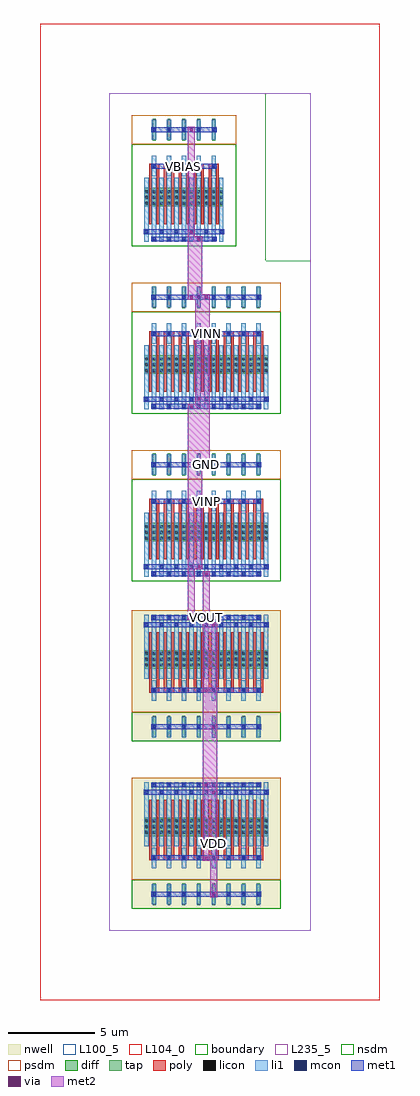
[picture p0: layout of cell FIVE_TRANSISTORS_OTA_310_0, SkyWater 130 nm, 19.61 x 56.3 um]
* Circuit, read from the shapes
.subckt FIVE_TRANSISTORS_OTA_310_0 GND VBIAS VDD VINN VINP VOUT
XM1 n1 VINP n2 GND sky130_fd_pr__nfet_01v8 w=1.05 l=0.15 m=16
XM2 VOUT VINN n2 GND sky130_fd_pr__nfet_01v8 w=1.05 l=0.15 m=16
XM3 n2 VBIAS GND GND sky130_fd_pr__nfet_01v8 w=1.05 l=0.15 m=10
XM4 n1 n1 VDD VDD sky130_fd_pr__pfet_01v8 w=1.05 l=0.15 m=16
XM5 VOUT n1 VDD VDD sky130_fd_pr__pfet_01v8 w=1.05 l=0.15 m=16
.ends

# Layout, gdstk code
import gdstk
lib = gdstk.Library(unit=1e-6, precision=1e-09)
def R(c, l, rs):  # rectangles x0, y0, x1, y1
    for r in rs: c.add(gdstk.rectangle(r[:2], r[2:], *l))
def A(c, l, x, y, w, h, nx, ny, dx, dy):  # array of equal rectangles
    R(c, l, [(x+i*dx, y+j*dy, x+i*dx+w, y+j*dy+h) for i in range(nx) for j in range(ny)])
def P(c, l, *ps):  # polygons
    for p in ps: c.add(gdstk.Polygon(p, *l))
nwell = (64, 20)
diff = (65, 20)
tap = (65, 44)
poly = (66, 20)
licon = (66, 44)
li1 = (67, 20)
mcon = (67, 44)
met1 = (68, 20)
via = (68, 44)
met2 = (69, 20)
nsdm = (93, 44)
psdm = (94, 20)
L100_5 = (100, 5)
L104_0 = (104, 0)
boundary = (235, 4)
L235_5 = (235, 5)

dcl_pmos_s_17530687_x8_y = lib.new_cell('DCL_PMOS_S_17530687_X8_Y1_1746750583')
R(dcl_pmos_s_17530687_x8_y, nwell, [(1.29,0.84,9.89,8.4)])
R(dcl_pmos_s_17530687_x8_y, diff, [(2.025,3.15,9.155,4.2)])
A(dcl_pmos_s_17530687_x8_y, tap, 2.495, 6.915, 0.17, 1.29, 8, 1, 0.86, 0)
A(dcl_pmos_s_17530687_x8_y, poly, 2.29, 2.1, 0.15, 3.36, 16, 1, 0.43, 0)
A(dcl_pmos_s_17530687_x8_y, poly, 2.29, 5.325, 0.58, 0.27, 8, 1, 0.86, 0)
A(dcl_pmos_s_17530687_x8_y, licon, 2.065, 3.23, 0.17, 0.17, 3, 3, 0.43, 0.34)
A(dcl_pmos_s_17530687_x8_y, licon, 2.925, 3.23, 0.17, 0.17, 3, 3, 0.43, 0.34)
A(dcl_pmos_s_17530687_x8_y, licon, 3.785, 3.23, 0.17, 0.17, 3, 3, 0.43, 0.34)
A(dcl_pmos_s_17530687_x8_y, licon, 4.645, 3.23, 0.17, 0.17, 3, 3, 0.43, 0.34)
A(dcl_pmos_s_17530687_x8_y, licon, 5.505, 3.23, 0.17, 0.17, 3, 3, 0.43, 0.34)
A(dcl_pmos_s_17530687_x8_y, licon, 6.365, 3.23, 0.17, 0.17, 3, 3, 0.43, 0.34)
A(dcl_pmos_s_17530687_x8_y, licon, 7.225, 3.23, 0.17, 0.17, 3, 3, 0.43, 0.34)
A(dcl_pmos_s_17530687_x8_y, licon, 8.085, 3.23, 0.17, 0.17, 3, 3, 0.43, 0.34)
A(dcl_pmos_s_17530687_x8_y, licon, 2.495, 5.375, 0.17, 0.17, 8, 2, 0.86, 2.1)
A(dcl_pmos_s_17530687_x8_y, li1, 2.025, 1.09, 0.25, 3.7, 17, 1, 0.43, 0)
A(dcl_pmos_s_17530687_x8_y, li1, 2.455, 4.87, 0.25, 1.18, 8, 2, 0.86, 2.1)
A(dcl_pmos_s_17530687_x8_y, mcon, 2.495, 1.175, 0.17, 0.17, 8, 2, 0.86, 4.2)
A(dcl_pmos_s_17530687_x8_y, mcon, 2.065, 1.595, 0.17, 0.17, 9, 1, 0.86, 0)
A(dcl_pmos_s_17530687_x8_y, mcon, 2.495, 7.475, 0.17, 0.17, 8, 1, 0.86, 0)
R(dcl_pmos_s_17530687_x8_y, met1, [(2.41,1.12,8.77,1.4), (1.98,1.54,9.2,1.82), (2.41,5.32,8.77,5.6), (2.41,7.42,8.77,7.7)])
R(dcl_pmos_s_17530687_x8_y, via, [(5.515,1.185,5.665,1.335), (5.945,1.605,6.095,1.755), (5.515,5.385,5.665,5.535), (5.945,7.485,6.095,7.635)])
R(dcl_pmos_s_17530687_x8_y, met2, [(5.39,1.1,5.79,5.62), (5.82,1.52,6.22,7.72)])
R(dcl_pmos_s_17530687_x8_y, nsdm, [(1.29,6.72,9.89,8.4)])
R(dcl_pmos_s_17530687_x8_y, psdm, [(1.29,0.84,9.89,6.72)])
R(dcl_pmos_s_17530687_x8_y, L100_5, [(0,0,11.61,9.66)])
R(dcl_pmos_s_17530687_x8_y, boundary, [(0,0,11.61,9.66)])

nmos_s_52209288_x5_y1_17 = lib.new_cell('NMOS_S_52209288_X5_Y1_1746750586')
R(nmos_s_52209288_x5_y1_17, diff, [(2.025,3.15,6.575,4.2)])
A(nmos_s_52209288_x5_y1_17, tap, 2.495, 6.915, 0.17, 1.29, 5, 1, 0.86, 0)
A(nmos_s_52209288_x5_y1_17, poly, 2.29, 2.1, 0.15, 3.36, 10, 1, 0.43, 0)
A(nmos_s_52209288_x5_y1_17, poly, 2.29, 5.325, 0.58, 0.27, 5, 1, 0.86, 0)
A(nmos_s_52209288_x5_y1_17, licon, 2.065, 3.23, 0.17, 0.17, 3, 3, 0.43, 0.34)
A(nmos_s_52209288_x5_y1_17, licon, 2.925, 3.23, 0.17, 0.17, 3, 3, 0.43, 0.34)
A(nmos_s_52209288_x5_y1_17, licon, 3.785, 3.23, 0.17, 0.17, 3, 3, 0.43, 0.34)
A(nmos_s_52209288_x5_y1_17, licon, 4.645, 3.23, 0.17, 0.17, 3, 3, 0.43, 0.34)
A(nmos_s_52209288_x5_y1_17, licon, 5.505, 3.23, 0.17, 0.17, 3, 3, 0.43, 0.34)
A(nmos_s_52209288_x5_y1_17, licon, 2.495, 5.375, 0.17, 0.17, 5, 2, 0.86, 2.1)
A(nmos_s_52209288_x5_y1_17, li1, 2.025, 1.09, 0.25, 3.7, 11, 1, 0.43, 0)
A(nmos_s_52209288_x5_y1_17, li1, 2.455, 4.87, 0.25, 1.18, 5, 2, 0.86, 2.1)
A(nmos_s_52209288_x5_y1_17, mcon, 2.495, 1.175, 0.17, 0.17, 5, 2, 0.86, 4.2)
A(nmos_s_52209288_x5_y1_17, mcon, 2.065, 1.595, 0.17, 0.17, 6, 1, 0.86, 0)
A(nmos_s_52209288_x5_y1_17, mcon, 2.495, 7.475, 0.17, 0.17, 5, 1, 0.86, 0)
R(nmos_s_52209288_x5_y1_17, met1, [(2.41,1.12,6.19,1.4), (1.98,1.54,6.62,1.82), (2.41,5.32,6.19,5.6), (2.41,7.42,6.19,7.7)])
R(nmos_s_52209288_x5_y1_17, via, [(4.655,1.605,4.805,1.755), (4.655,7.485,4.805,7.635)])
R(nmos_s_52209288_x5_y1_17, met2, [(4.53,1.52,4.93,7.72)])
R(nmos_s_52209288_x5_y1_17, nsdm, [(1.29,0.84,7.31,6.72)])
R(nmos_s_52209288_x5_y1_17, psdm, [(1.29,6.72,7.31,8.4)])
R(nmos_s_52209288_x5_y1_17, L100_5, [(0,0,9.03,9.66)])
R(nmos_s_52209288_x5_y1_17, boundary, [(0,0,9.03,9.66)])

pmos_s_93182587_x8_y1_17 = lib.new_cell('PMOS_S_93182587_X8_Y1_1746750587')
R(pmos_s_93182587_x8_y1_17, nwell, [(1.29,0.84,9.89,8.4)])
R(pmos_s_93182587_x8_y1_17, diff, [(2.025,3.15,9.155,4.2)])
A(pmos_s_93182587_x8_y1_17, tap, 2.495, 6.915, 0.17, 1.29, 8, 1, 0.86, 0)
A(pmos_s_93182587_x8_y1_17, poly, 2.29, 2.1, 0.15, 3.36, 16, 1, 0.43, 0)
A(pmos_s_93182587_x8_y1_17, poly, 2.29, 5.325, 0.58, 0.27, 8, 1, 0.86, 0)
A(pmos_s_93182587_x8_y1_17, licon, 2.065, 3.23, 0.17, 0.17, 3, 3, 0.43, 0.34)
A(pmos_s_93182587_x8_y1_17, licon, 2.925, 3.23, 0.17, 0.17, 3, 3, 0.43, 0.34)
A(pmos_s_93182587_x8_y1_17, licon, 3.785, 3.23, 0.17, 0.17, 3, 3, 0.43, 0.34)
A(pmos_s_93182587_x8_y1_17, licon, 4.645, 3.23, 0.17, 0.17, 3, 3, 0.43, 0.34)
A(pmos_s_93182587_x8_y1_17, licon, 5.505, 3.23, 0.17, 0.17, 3, 3, 0.43, 0.34)
A(pmos_s_93182587_x8_y1_17, licon, 6.365, 3.23, 0.17, 0.17, 3, 3, 0.43, 0.34)
A(pmos_s_93182587_x8_y1_17, licon, 7.225, 3.23, 0.17, 0.17, 3, 3, 0.43, 0.34)
A(pmos_s_93182587_x8_y1_17, licon, 8.085, 3.23, 0.17, 0.17, 3, 3, 0.43, 0.34)
A(pmos_s_93182587_x8_y1_17, licon, 2.495, 5.375, 0.17, 0.17, 8, 2, 0.86, 2.1)
A(pmos_s_93182587_x8_y1_17, li1, 2.025, 1.09, 0.25, 3.7, 17, 1, 0.43, 0)
A(pmos_s_93182587_x8_y1_17, li1, 2.455, 4.87, 0.25, 1.18, 8, 2, 0.86, 2.1)
A(pmos_s_93182587_x8_y1_17, mcon, 2.495, 1.175, 0.17, 0.17, 8, 2, 0.86, 4.2)
A(pmos_s_93182587_x8_y1_17, mcon, 2.065, 1.595, 0.17, 0.17, 9, 1, 0.86, 0)
A(pmos_s_93182587_x8_y1_17, mcon, 2.495, 7.475, 0.17, 0.17, 8, 1, 0.86, 0)
R(pmos_s_93182587_x8_y1_17, met1, [(2.41,1.12,8.77,1.4), (1.98,1.54,9.2,1.82), (2.41,5.32,8.77,5.6), (2.41,7.42,8.77,7.7)])
R(pmos_s_93182587_x8_y1_17, via, [(5.945,1.605,6.095,1.755), (5.945,7.485,6.095,7.635)])
R(pmos_s_93182587_x8_y1_17, met2, [(5.82,1.52,6.22,7.72)])
R(pmos_s_93182587_x8_y1_17, nsdm, [(1.29,6.72,9.89,8.4)])
R(pmos_s_93182587_x8_y1_17, psdm, [(1.29,0.84,9.89,6.72)])
R(pmos_s_93182587_x8_y1_17, L100_5, [(0,0,11.61,9.66)])
R(pmos_s_93182587_x8_y1_17, boundary, [(0,0,11.61,9.66)])

nmos_4t_3160949_x8_y1_17 = lib.new_cell('NMOS_4T_3160949_X8_Y1_1746750585')
R(nmos_4t_3160949_x8_y1_17, diff, [(2.025,3.15,9.155,4.2)])
A(nmos_4t_3160949_x8_y1_17, tap, 2.495, 6.915, 0.17, 1.29, 8, 1, 0.86, 0)
A(nmos_4t_3160949_x8_y1_17, poly, 2.29, 2.1, 0.15, 3.36, 16, 1, 0.43, 0)
A(nmos_4t_3160949_x8_y1_17, poly, 2.29, 5.325, 0.58, 0.27, 8, 1, 0.86, 0)
A(nmos_4t_3160949_x8_y1_17, licon, 2.065, 3.23, 0.17, 0.17, 3, 3, 0.43, 0.34)
A(nmos_4t_3160949_x8_y1_17, licon, 2.925, 3.23, 0.17, 0.17, 3, 3, 0.43, 0.34)
A(nmos_4t_3160949_x8_y1_17, licon, 3.785, 3.23, 0.17, 0.17, 3, 3, 0.43, 0.34)
A(nmos_4t_3160949_x8_y1_17, licon, 4.645, 3.23, 0.17, 0.17, 3, 3, 0.43, 0.34)
A(nmos_4t_3160949_x8_y1_17, licon, 5.505, 3.23, 0.17, 0.17, 3, 3, 0.43, 0.34)
A(nmos_4t_3160949_x8_y1_17, licon, 6.365, 3.23, 0.17, 0.17, 3, 3, 0.43, 0.34)
A(nmos_4t_3160949_x8_y1_17, licon, 7.225, 3.23, 0.17, 0.17, 3, 3, 0.43, 0.34)
A(nmos_4t_3160949_x8_y1_17, licon, 8.085, 3.23, 0.17, 0.17, 3, 3, 0.43, 0.34)
A(nmos_4t_3160949_x8_y1_17, licon, 2.495, 5.375, 0.17, 0.17, 8, 2, 0.86, 2.1)
A(nmos_4t_3160949_x8_y1_17, li1, 2.025, 1.09, 0.25, 3.7, 17, 1, 0.43, 0)
A(nmos_4t_3160949_x8_y1_17, li1, 2.455, 4.87, 0.25, 1.18, 8, 2, 0.86, 2.1)
A(nmos_4t_3160949_x8_y1_17, mcon, 2.495, 1.175, 0.17, 0.17, 8, 2, 0.86, 4.2)
A(nmos_4t_3160949_x8_y1_17, mcon, 2.065, 1.595, 0.17, 0.17, 9, 1, 0.86, 0)
A(nmos_4t_3160949_x8_y1_17, mcon, 2.495, 7.475, 0.17, 0.17, 8, 1, 0.86, 0)
R(nmos_4t_3160949_x8_y1_17, met1, [(2.41,1.12,8.77,1.4), (1.98,1.54,9.2,1.82), (2.41,5.32,8.77,5.6), (2.41,7.42,8.77,7.7)])
R(nmos_4t_3160949_x8_y1_17, nsdm, [(1.29,0.84,9.89,6.72)])
R(nmos_4t_3160949_x8_y1_17, psdm, [(1.29,6.72,9.89,8.4)])
R(nmos_4t_3160949_x8_y1_17, L100_5, [(0,0,11.61,9.66)])
R(nmos_4t_3160949_x8_y1_17, boundary, [(0,0,11.61,9.66)])

nmos_4t_21140221_x8_y1_1 = lib.new_cell('NMOS_4T_21140221_X8_Y1_1746750584')
R(nmos_4t_21140221_x8_y1_1, diff, [(2.025,3.15,9.155,4.2)])
A(nmos_4t_21140221_x8_y1_1, tap, 2.495, 6.915, 0.17, 1.29, 8, 1, 0.86, 0)
A(nmos_4t_21140221_x8_y1_1, poly, 2.29, 2.1, 0.15, 3.36, 16, 1, 0.43, 0)
A(nmos_4t_21140221_x8_y1_1, poly, 2.29, 5.325, 0.58, 0.27, 8, 1, 0.86, 0)
A(nmos_4t_21140221_x8_y1_1, licon, 2.065, 3.23, 0.17, 0.17, 3, 3, 0.43, 0.34)
A(nmos_4t_21140221_x8_y1_1, licon, 2.925, 3.23, 0.17, 0.17, 3, 3, 0.43, 0.34)
A(nmos_4t_21140221_x8_y1_1, licon, 3.785, 3.23, 0.17, 0.17, 3, 3, 0.43, 0.34)
A(nmos_4t_21140221_x8_y1_1, licon, 4.645, 3.23, 0.17, 0.17, 3, 3, 0.43, 0.34)
A(nmos_4t_21140221_x8_y1_1, licon, 5.505, 3.23, 0.17, 0.17, 3, 3, 0.43, 0.34)
A(nmos_4t_21140221_x8_y1_1, licon, 6.365, 3.23, 0.17, 0.17, 3, 3, 0.43, 0.34)
A(nmos_4t_21140221_x8_y1_1, licon, 7.225, 3.23, 0.17, 0.17, 3, 3, 0.43, 0.34)
A(nmos_4t_21140221_x8_y1_1, licon, 8.085, 3.23, 0.17, 0.17, 3, 3, 0.43, 0.34)
A(nmos_4t_21140221_x8_y1_1, licon, 2.495, 5.375, 0.17, 0.17, 8, 2, 0.86, 2.1)
A(nmos_4t_21140221_x8_y1_1, li1, 2.025, 1.09, 0.25, 3.7, 17, 1, 0.43, 0)
A(nmos_4t_21140221_x8_y1_1, li1, 2.455, 4.87, 0.25, 1.18, 8, 2, 0.86, 2.1)
A(nmos_4t_21140221_x8_y1_1, mcon, 2.495, 1.175, 0.17, 0.17, 8, 2, 0.86, 4.2)
A(nmos_4t_21140221_x8_y1_1, mcon, 2.065, 1.595, 0.17, 0.17, 9, 1, 0.86, 0)
A(nmos_4t_21140221_x8_y1_1, mcon, 2.495, 7.475, 0.17, 0.17, 8, 1, 0.86, 0)
R(nmos_4t_21140221_x8_y1_1, met1, [(2.41,1.12,8.77,1.4), (1.98,1.54,9.2,1.82), (2.41,5.32,8.77,5.6), (2.41,7.42,8.77,7.7)])
R(nmos_4t_21140221_x8_y1_1, nsdm, [(1.29,0.84,9.89,6.72)])
R(nmos_4t_21140221_x8_y1_1, psdm, [(1.29,6.72,9.89,8.4)])
R(nmos_4t_21140221_x8_y1_1, L100_5, [(0,0,11.61,9.66)])
R(nmos_4t_21140221_x8_y1_1, boundary, [(0,0,11.61,9.66)])

five_transistors_ota_310 = lib.new_cell('FIVE_TRANSISTORS_OTA_310_0')
R(five_transistors_ota_310, met1, [(5.43,13.72,5.75,14), (5.43,13.72,5.75,14), (5.43,13.72,5.75,14), (5.43,13.72,5.75,14), (4.57,17.92,4.89,18.2), (4.57,17.92,4.89,18.2), (5.43,20.44,5.75,20.72), (5.43,20.44,5.75,20.72), (5,20.86,5.32,21.14), (5,20.86,5.32,21.14), (5,20.86,5.32,21.14), (5,20.86,5.32,21.14), (5.43,26.74,5.75,27.02), (5.43,26.74,5.75,27.02), (5.43,26.74,5.75,27.02), (5.43,26.74,5.75,27.02), (4.57,30.1,4.89,30.38), (4.57,30.1,4.89,30.38), (5,30.52,5.32,30.8), (5,30.52,5.32,30.8), (5,30.52,5.32,30.8), (5,30.52,5.32,30.8), (4.57,36.4,4.89,36.68), (4.57,36.4,4.89,36.68), (5.43,36.4,5.75,36.68), (5.43,36.4,5.75,36.68), (5.43,36.4,5.75,36.68), (5.43,36.4,5.75,36.68), (5,39.76,5.32,40.04), (5,39.76,5.32,40.04)])
P(five_transistors_ota_310, met1, [(0,0),(0,0),(0,0),(0,0)],
  [(0,0),(0,0),(0,0),(0,0)],
  [(0,0),(0,0),(0,0),(0,0)],
  [(0,0),(0,0),(0,0),(0,0)],
  [(0,0),(0,0),(0,0),(0,0)],
  [(0,0),(0,0),(0,0),(0,0)],
  [(0,0),(0,0),(0,0),(0,0)],
  [(0,0),(0,0),(0,0),(0,0)],
  [(0,0),(0,0),(0,0),(0,0)],
  [(0,0),(0,0),(0,0),(0,0)],
  [(0,0),(0,0),(0,0),(0,0)],
  [(0,0),(0,0),(0,0),(0,0)],
  [(0,0),(0,0),(0,0),(0,0)],
  [(0,0),(0,0),(0,0),(0,0)],
  [(0,0),(0,0),(0,0),(0,0)],
  [(0,0),(0,0),(0,0),(0,0)],
  [(0,0),(0,0),(0,0),(0,0)])
R(five_transistors_ota_310, via, [(5.515,13.785,5.665,13.935), (5.515,13.785,5.665,13.935), (5.515,13.785,5.665,13.935), (5.515,13.785,5.665,13.935), (4.655,17.985,4.805,18.135), (4.655,17.985,4.805,18.135), (5.515,20.505,5.665,20.655), (5.515,20.505,5.665,20.655), (5.085,20.925,5.235,21.075), (5.085,20.925,5.235,21.075), (5.085,20.925,5.235,21.075), (5.085,20.925,5.235,21.075), (5.515,26.805,5.665,26.955), (5.515,26.805,5.665,26.955), (5.515,26.805,5.665,26.955), (5.515,26.805,5.665,26.955), (4.655,30.165,4.805,30.315), (4.655,30.165,4.805,30.315), (5.085,30.585,5.235,30.735), (5.085,30.585,5.235,30.735), (5.085,30.585,5.235,30.735), (5.085,30.585,5.235,30.735), (4.655,36.465,4.805,36.615), (4.655,36.465,4.805,36.615), (5.515,36.465,5.665,36.615), (5.515,36.465,5.665,36.615), (5.515,36.465,5.665,36.615), (5.515,36.465,5.665,36.615), (5.085,39.825,5.235,39.975), (5.085,39.825,5.235,39.975)])
R(five_transistors_ota_310, met2, [(5.82,7.98,6.22,11.76), (5.39,8.4,5.79,13.86), (5.39,13.7,5.79,14.02), (5.39,13.7,5.79,14.02), (5.39,13.7,5.79,14.02), (5.39,13.7,5.79,14.02), (5.39,13.86,5.79,20.58), (4.53,17.9,4.93,18.22), (4.53,17.9,4.93,18.22), (4.53,18.06,4.93,30.24), (5.39,20.42,5.79,20.74), (5.39,20.42,5.79,20.74), (4.96,20.84,5.36,21.16), (4.96,20.84,5.36,21.16), (4.96,20.84,5.36,21.16), (4.96,20.84,5.36,21.16), (4.96,21,5.36,30.66), (5.39,26.72,5.79,27.04), (5.39,26.72,5.79,27.04), (5.39,26.72,5.79,27.04), (5.39,26.72,5.79,27.04), (5.39,26.88,5.79,36.54), (4.53,30.08,4.93,30.4), (4.53,30.08,4.93,30.4), (4.96,30.5,5.36,30.82), (4.96,30.5,5.36,30.82), (4.96,30.5,5.36,30.82), (4.96,30.5,5.36,30.82), (4.96,30.66,5.36,39.9), (4.53,36.38,4.93,36.7), (4.53,36.38,4.93,36.7), (5.39,36.38,5.79,36.7), (5.39,36.38,5.79,36.7), (5.39,36.38,5.79,36.7), (5.39,36.38,5.79,36.7), (4.53,36.54,4.93,40.32), (4.96,39.74,5.36,40.06), (4.96,39.74,5.36,40.06)])
P(five_transistors_ota_310, met2, [(0,0),(0,0),(0,0),(0,0)],
  [(0,0),(0,0),(0,0),(0,0)],
  [(0,0),(0,0),(0,0),(0,0)],
  [(0,0),(0,0),(0,0),(0,0)],
  [(0,0),(0,0),(0,0),(0,0)])
R(five_transistors_ota_310, L104_0, [(-4,-4,15.61,52.3)])
R(five_transistors_ota_310, L235_5, [(0,0,11.61,48.3)])
five_transistors_ota_310.add(gdstk.Reference(dcl_pmos_s_17530687_x8_y, (0,9.66), x_reflection=True))
five_transistors_ota_310.add(gdstk.Reference(nmos_s_52209288_x5_y1_17, (0,38.64)))
five_transistors_ota_310.add(gdstk.Reference(pmos_s_93182587_x8_y1_17, (0,19.32), x_reflection=True))
five_transistors_ota_310.add(gdstk.Reference(nmos_4t_3160949_x8_y1_17, (0,28.98)))
five_transistors_ota_310.add(gdstk.Reference(nmos_4t_21140221_x8_y1_1, (0,19.32)))
five_transistors_ota_310.add(gdstk.Label('VDD', (6.02,5.04), layer=69, texttype=5))
five_transistors_ota_310.add(gdstk.Label('VBIAS', (4.3,44.1), layer=68, texttype=5))
five_transistors_ota_310.add(gdstk.Label('GND', (5.59,26.88), layer=68, texttype=5))
five_transistors_ota_310.add(gdstk.Label('VOUT', (5.59,18.06), layer=68, texttype=5))
five_transistors_ota_310.add(gdstk.Label('VINN', (5.59,34.44), layer=68, texttype=5))
five_transistors_ota_310.add(gdstk.Label('VINP', (5.59,24.78), layer=68, texttype=5))

lib.write_gds('FIVE_TRANSISTORS_OTA_310_0.gds')
